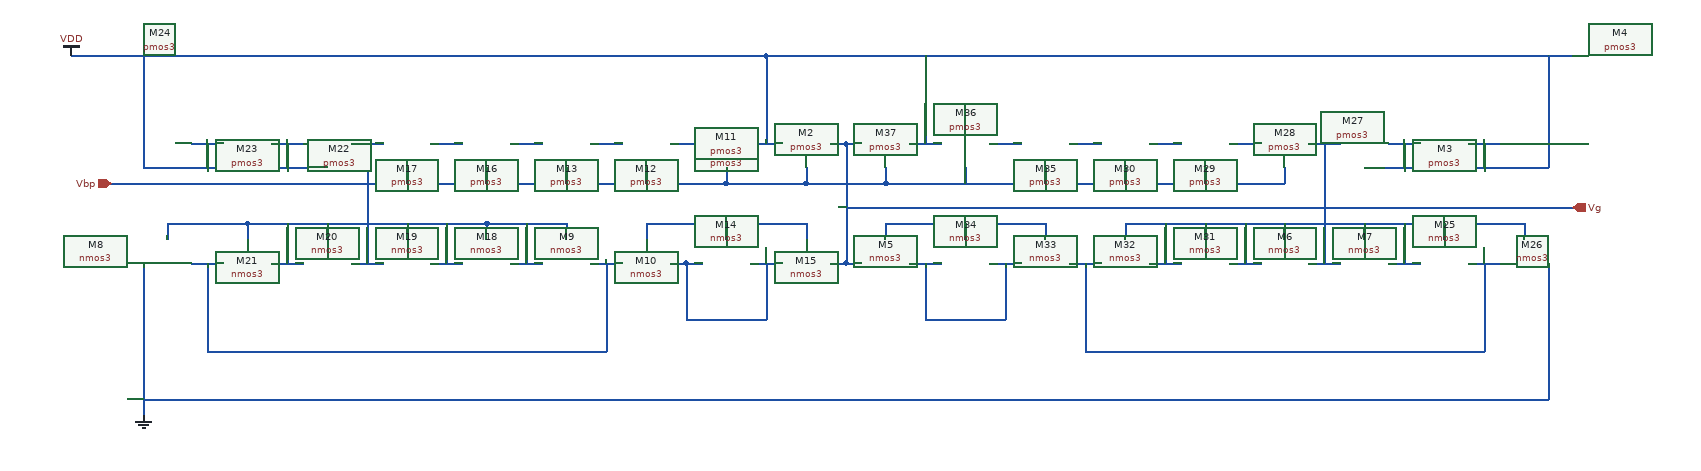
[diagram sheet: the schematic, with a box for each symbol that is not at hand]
v {xschem version=2.9.9 file_version=1.2 }
G {}
K {}
V {}
S {}
E {}
N 1330 -540 1330 -520 { lab=Vbp}
N 1330 -520 1430 -520 { lab=Vbp}
N 1430 -540 1430 -520 { lab=Vbp}
N 1110 -520 1330 -520 { lab=Vbp}
N 1360 -570 1400 -570 { lab=VDD}
N 1380 -680 1380 -570 { lab=VDD}
N 1110 -680 1380 -680 { lab=VDD}
N 1460 -570 1480 -570 { lab=Vg}
N 1480 -570 1480 -420 { lab=Vg}
N 1260 -420 1280 -420 { lab=#net1}
N 1230 -470 1230 -450 { lab=#net2}
N 1230 -470 1280 -470 { lab=#net2}
N 1160 -420 1200 -420 { lab=#net3}
N 1180 -420 1180 -340 { lab=#net3}
N 630 -470 630 -450 { lab=#net4}
N 1030 -470 1130 -470 { lab=#net4}
N 1130 -470 1130 -450 { lab=#net4}
N 1280 -420 1300 -420 { lab=#net1}
N 1280 -420 1280 -350 { lab=#net1}
N 1280 -350 1380 -350 { lab=#net1}
N 1380 -420 1380 -350 { lab=#net1}
N 1360 -420 1400 -420 { lab=#net1}
N 1280 -470 1430 -470 { lab=#net2}
N 1430 -470 1430 -450 { lab=#net2}
N 1330 -470 1330 -450 { lab=#net2}
N 1460 -420 1480 -420 { lab=Vg}
N 850 -680 1110 -680 { lab=VDD}
N 850 -520 1110 -520 { lab=Vbp}
N 1260 -570 1300 -570 { lab=#net5}
N 1160 -570 1200 -570 { lab=#net6}
N 1060 -570 1100 -570 { lab=#net7}
N 960 -570 1000 -570 { lab=#net8}
N 930 -540 930 -520 { lab=Vbp}
N 1030 -540 1030 -520 { lab=Vbp}
N 1130 -540 1130 -520 { lab=Vbp}
N 1230 -540 1230 -520 { lab=Vbp}
N 960 -420 1000 -420 { lab=#net4}
N 860 -420 900 -420 { lab=#net4}
N 760 -420 800 -420 { lab=#net4}
N 1180 -340 1180 -310 { lab=#net3}
N 1060 -420 1100 -420 { lab=#net4}
N 730 -470 1030 -470 { lab=#net4}
N 730 -470 730 -450 { lab=#net4}
N 830 -470 830 -450 { lab=#net4}
N 930 -470 930 -450 { lab=#net4}
N 1030 -470 1030 -450 { lab=#net4}
N 1080 -470 1080 -420 { lab=#net4}
N 980 -470 980 -420 { lab=#net4}
N 880 -470 880 -420 { lab=#net4}
N 780 -470 780 -420 { lab=#net4}
N 630 -470 730 -470 { lab=#net4}
N 660 -420 700 -420 { lab=#net3}
N 680 -420 680 -310 { lab=#net3}
N 680 -310 1180 -310 { lab=#net3}
N 880 -570 900 -570 { lab=#net4}
N 880 -570 880 -470 { lab=#net4}
N 560 -520 850 -520 { lab=Vbp}
N 860 -570 880 -570 { lab=#net4}
N 760 -570 800 -570 { lab=VDD}
N 660 -570 700 -570 { lab=VDD}
N 600 -570 600 -540 { lab=VDD}
N 600 -540 830 -540 { lab=VDD}
N 600 -680 600 -570 { lab=VDD}
N 510 -680 850 -680 { lab=VDD}
N 680 -570 680 -540 { lab=VDD}
N 780 -570 780 -540 { lab=VDD}
N 1480 -420 1500 -420 { lab=Vg}
N 1480 -570 1500 -570 { lab=Vg}
N 1560 -570 1600 -570 { lab=VDD}
N 1560 -420 1600 -420 { lab=#net9}
N 1660 -570 1700 -570 { lab=#net10}
N 1660 -420 1700 -420 { lab=#net9}
N 1760 -570 1800 -570 { lab=#net11}
N 1760 -420 1800 -420 { lab=#net12}
N 1860 -570 1900 -570 { lab=#net13}
N 1860 -420 1900 -420 { lab=#net14}
N 1960 -570 2000 -570 { lab=#net15}
N 1960 -420 2000 -420 { lab=#net14}
N 2060 -570 2100 -570 { lab=#net14}
N 2060 -420 2100 -420 { lab=#net14}
N 2160 -570 2200 -570 { lab=VDD}
N 2160 -420 2200 -420 { lab=#net14}
N 2260 -570 2300 -570 { lab=VDD}
N 2260 -420 2300 -420 { lab=#net12}
N 1530 -470 1530 -450 { lab=#net16}
N 1530 -470 1730 -470 { lab=#net16}
N 1730 -470 1730 -450 { lab=#net16}
N 1630 -470 1630 -450 { lab=#net16}
N 1580 -420 1580 -350 { lab=#net9}
N 1580 -350 1680 -350 { lab=#net9}
N 1680 -420 1680 -350 { lab=#net9}
N 1580 -680 1580 -570 { lab=VDD}
N 1380 -680 2390 -680 { lab=VDD}
N 1530 -540 1530 -520 { lab=Vbp}
N 1530 -520 2030 -520 { lab=Vbp}
N 2030 -540 2030 -520 { lab=Vbp}
N 1630 -540 1630 -520 { lab=Vbp}
N 1730 -540 1730 -520 { lab=Vbp}
N 1830 -540 1830 -520 { lab=Vbp}
N 1930 -540 1930 -520 { lab=Vbp}
N 1430 -520 1530 -520 { lab=Vbp}
N 2130 -540 2230 -540 { lab=VDD}
N 2230 -540 2330 -540 { lab=VDD}
N 2330 -540 2360 -540 { lab=VDD}
N 2360 -680 2360 -540 { lab=VDD}
N 2180 -570 2180 -540 { lab=VDD}
N 2280 -570 2280 -540 { lab=VDD}
N 1780 -420 1780 -310 { lab=#net12}
N 1780 -310 2280 -310 { lab=#net12}
N 2280 -420 2280 -310 { lab=#net12}
N 2360 -420 2360 -250 { lab=#net17}
N 1830 -470 1830 -450 { lab=#net14}
N 1830 -470 2330 -470 { lab=#net14}
N 2330 -470 2330 -450 { lab=#net14}
N 2230 -470 2230 -450 { lab=#net14}
N 2130 -470 2130 -450 { lab=#net14}
N 2030 -470 2030 -450 { lab=#net14}
N 1930 -470 1930 -450 { lab=#net14}
N 1880 -470 1880 -420 { lab=#net14}
N 1980 -470 1980 -420 { lab=#net14}
N 2080 -470 2080 -420 { lab=#net14}
N 2180 -470 2180 -420 { lab=#net14}
N 2080 -570 2080 -470 { lab=#net14}
N 1480 -490 2390 -490 { lab=Vg}
N 600 -420 600 -230 { lab=#net18}
N 600 -250 2360 -250 {}
C {madvlsi/pmos3.sym} 1330 -570 3 0 {name=M1
L=1
W=1.5
body=VDD
nf=1
mult=1
ad="'int((nf+1)/2) * W/nf * 0.29'" 
pd="'2*int((nf+1)/2) * (W/nf + 0.29)'"
as="'int((nf+2)/2) * W/nf * 0.29'" 
ps="'2*int((nf+2)/2) * (W/nf + 0.29)'"
nrd="'0.29 / W'" nrs="'0.29 / W'"
sa=0 sb=0 sd=0
model=pfet_01v8
spiceprefix=X
}
C {madvlsi/pmos3.sym} 1430 -570 3 0 {name=M2
L=1
W=1.5
body=VDD
nf=1
mult=1
ad="'int((nf+1)/2) * W/nf * 0.29'" 
pd="'2*int((nf+1)/2) * (W/nf + 0.29)'"
as="'int((nf+2)/2) * W/nf * 0.29'" 
ps="'2*int((nf+2)/2) * (W/nf + 0.29)'"
nrd="'0.29 / W'" nrs="'0.29 / W'"
sa=0 sb=0 sd=0
model=pfet_01v8
spiceprefix=X
}
C {madvlsi/nmos3.sym} 630 -420 1 0 {name=M8
L=1
W=3
body=GND
nf=1
mult=3
ad="'int((nf+1)/2) * W/nf * 0.29'" 
pd="'2*int((nf+1)/2) * (W/nf + 0.29)'"
as="'int((nf+2)/2) * W/nf * 0.29'" 
ps="'2*int((nf+2)/2) * (W/nf + 0.29)'"
nrd="'0.29 / W'" nrs="'0.29 / W'"
sa=0 sb=0 sd=0
model=nfet_01v8
spiceprefix=X
}
C {madvlsi/nmos3.sym} 1130 -420 1 0 {name=M9
L=1
W=3
body=GND
nf=1
mult=3
ad="'int((nf+1)/2) * W/nf * 0.29'" 
pd="'2*int((nf+1)/2) * (W/nf + 0.29)'"
as="'int((nf+2)/2) * W/nf * 0.29'" 
ps="'2*int((nf+2)/2) * (W/nf + 0.29)'"
nrd="'0.29 / W'" nrs="'0.29 / W'"
sa=0 sb=0 sd=0
model=nfet_01v8
spiceprefix=X
}
C {madvlsi/nmos3.sym} 1230 -420 1 0 {name=M10
L=1
W=3
body=GND
nf=1
mult=3
ad="'int((nf+1)/2) * W/nf * 0.29'" 
pd="'2*int((nf+1)/2) * (W/nf + 0.29)'"
as="'int((nf+2)/2) * W/nf * 0.29'" 
ps="'2*int((nf+2)/2) * (W/nf + 0.29)'"
nrd="'0.29 / W'" nrs="'0.29 / W'"
sa=0 sb=0 sd=0
model=nfet_01v8
spiceprefix=X
}
C {madvlsi/vdd.sym} 510 -680 0 0 {name=l1 lab=VDD}
C {madvlsi/pmos3.sym} 1330 -570 3 0 {name=M11
L=1
W=1.5
body=VDD
nf=1
mult=1
ad="'int((nf+1)/2) * W/nf * 0.29'" 
pd="'2*int((nf+1)/2) * (W/nf + 0.29)'"
as="'int((nf+2)/2) * W/nf * 0.29'" 
ps="'2*int((nf+2)/2) * (W/nf + 0.29)'"
nrd="'0.29 / W'" nrs="'0.29 / W'"
sa=0 sb=0 sd=0
model=pfet_01v8
spiceprefix=X
}
C {devices/ipin.sym} 560 -520 0 0 {name=p1 lab=Vbp}
C {madvlsi/gnd.sym} 600 -230 0 0 {name=l2 lab=GND}
C {devices/opin.sym} 2390 -490 0 0 {name=p2 lab=Vg}
C {madvlsi/nmos3.sym} 1330 -420 1 0 {name=M14
L=1
W=3
body=GND
nf=1
mult=3
ad="'int((nf+1)/2) * W/nf * 0.29'" 
pd="'2*int((nf+1)/2) * (W/nf + 0.29)'"
as="'int((nf+2)/2) * W/nf * 0.29'" 
ps="'2*int((nf+2)/2) * (W/nf + 0.29)'"
nrd="'0.29 / W'" nrs="'0.29 / W'"
sa=0 sb=0 sd=0
model=nfet_01v8
spiceprefix=X
}
C {madvlsi/nmos3.sym} 1430 -420 1 0 {name=M15
L=1
W=3
body=GND
nf=1
mult=3
ad="'int((nf+1)/2) * W/nf * 0.29'" 
pd="'2*int((nf+1)/2) * (W/nf + 0.29)'"
as="'int((nf+2)/2) * W/nf * 0.29'" 
ps="'2*int((nf+2)/2) * (W/nf + 0.29)'"
nrd="'0.29 / W'" nrs="'0.29 / W'"
sa=0 sb=0 sd=0
model=nfet_01v8
spiceprefix=X
}
C {madvlsi/pmos3.sym} 1230 -570 3 0 {name=M12
L=1
W=1.5
body=VDD
nf=1
mult=1
ad="'int((nf+1)/2) * W/nf * 0.29'" 
pd="'2*int((nf+1)/2) * (W/nf + 0.29)'"
as="'int((nf+2)/2) * W/nf * 0.29'" 
ps="'2*int((nf+2)/2) * (W/nf + 0.29)'"
nrd="'0.29 / W'" nrs="'0.29 / W'"
sa=0 sb=0 sd=0
model=pfet_01v8
spiceprefix=X
}
C {madvlsi/pmos3.sym} 1130 -570 3 0 {name=M13
L=1
W=1.5
body=VDD
nf=1
mult=1
ad="'int((nf+1)/2) * W/nf * 0.29'" 
pd="'2*int((nf+1)/2) * (W/nf + 0.29)'"
as="'int((nf+2)/2) * W/nf * 0.29'" 
ps="'2*int((nf+2)/2) * (W/nf + 0.29)'"
nrd="'0.29 / W'" nrs="'0.29 / W'"
sa=0 sb=0 sd=0
model=pfet_01v8
spiceprefix=X
}
C {madvlsi/pmos3.sym} 1030 -570 3 0 {name=M16
L=1
W=1.5
body=VDD
nf=1
mult=1
ad="'int((nf+1)/2) * W/nf * 0.29'" 
pd="'2*int((nf+1)/2) * (W/nf + 0.29)'"
as="'int((nf+2)/2) * W/nf * 0.29'" 
ps="'2*int((nf+2)/2) * (W/nf + 0.29)'"
nrd="'0.29 / W'" nrs="'0.29 / W'"
sa=0 sb=0 sd=0
model=pfet_01v8
spiceprefix=X
}
C {madvlsi/pmos3.sym} 930 -570 3 0 {name=M17
L=1
W=1.5
body=VDD
nf=1
mult=1
ad="'int((nf+1)/2) * W/nf * 0.29'" 
pd="'2*int((nf+1)/2) * (W/nf + 0.29)'"
as="'int((nf+2)/2) * W/nf * 0.29'" 
ps="'2*int((nf+2)/2) * (W/nf + 0.29)'"
nrd="'0.29 / W'" nrs="'0.29 / W'"
sa=0 sb=0 sd=0
model=pfet_01v8
spiceprefix=X
}
C {madvlsi/nmos3.sym} 1030 -420 1 0 {name=M18
L=1
W=3
body=GND
nf=1
mult=3
ad="'int((nf+1)/2) * W/nf * 0.29'" 
pd="'2*int((nf+1)/2) * (W/nf + 0.29)'"
as="'int((nf+2)/2) * W/nf * 0.29'" 
ps="'2*int((nf+2)/2) * (W/nf + 0.29)'"
nrd="'0.29 / W'" nrs="'0.29 / W'"
sa=0 sb=0 sd=0
model=nfet_01v8
spiceprefix=X
}
C {madvlsi/nmos3.sym} 930 -420 1 0 {name=M19
L=1
W=3
body=GND
nf=1
mult=3
ad="'int((nf+1)/2) * W/nf * 0.29'" 
pd="'2*int((nf+1)/2) * (W/nf + 0.29)'"
as="'int((nf+2)/2) * W/nf * 0.29'" 
ps="'2*int((nf+2)/2) * (W/nf + 0.29)'"
nrd="'0.29 / W'" nrs="'0.29 / W'"
sa=0 sb=0 sd=0
model=nfet_01v8
spiceprefix=X
}
C {madvlsi/nmos3.sym} 830 -420 1 0 {name=M20
L=1
W=3
body=GND
nf=1
mult=3
ad="'int((nf+1)/2) * W/nf * 0.29'" 
pd="'2*int((nf+1)/2) * (W/nf + 0.29)'"
as="'int((nf+2)/2) * W/nf * 0.29'" 
ps="'2*int((nf+2)/2) * (W/nf + 0.29)'"
nrd="'0.29 / W'" nrs="'0.29 / W'"
sa=0 sb=0 sd=0
model=nfet_01v8
spiceprefix=X
}
C {madvlsi/nmos3.sym} 730 -420 1 0 {name=M21
L=1
W=3
body=GND
nf=1
mult=3
ad="'int((nf+1)/2) * W/nf * 0.29'" 
pd="'2*int((nf+1)/2) * (W/nf + 0.29)'"
as="'int((nf+2)/2) * W/nf * 0.29'" 
ps="'2*int((nf+2)/2) * (W/nf + 0.29)'"
nrd="'0.29 / W'" nrs="'0.29 / W'"
sa=0 sb=0 sd=0
model=nfet_01v8
spiceprefix=X
}
C {madvlsi/pmos3.sym} 830 -570 3 0 {name=M22
L=1
W=1.5
body=VDD
nf=1
mult=1
ad="'int((nf+1)/2) * W/nf * 0.29'" 
pd="'2*int((nf+1)/2) * (W/nf + 0.29)'"
as="'int((nf+2)/2) * W/nf * 0.29'" 
ps="'2*int((nf+2)/2) * (W/nf + 0.29)'"
nrd="'0.29 / W'" nrs="'0.29 / W'"
sa=0 sb=0 sd=0
model=pfet_01v8
spiceprefix=X
}
C {madvlsi/pmos3.sym} 730 -570 3 0 {name=M23
L=1
W=1.5
body=VDD
nf=1
mult=1
ad="'int((nf+1)/2) * W/nf * 0.29'" 
pd="'2*int((nf+1)/2) * (W/nf + 0.29)'"
as="'int((nf+2)/2) * W/nf * 0.29'" 
ps="'2*int((nf+2)/2) * (W/nf + 0.29)'"
nrd="'0.29 / W'" nrs="'0.29 / W'"
sa=0 sb=0 sd=0
model=pfet_01v8
spiceprefix=X
}
C {madvlsi/pmos3.sym} 630 -570 3 0 {name=M24
L=1
W=1.5
body=VDD
nf=1
mult=1
ad="'int((nf+1)/2) * W/nf * 0.29'" 
pd="'2*int((nf+1)/2) * (W/nf + 0.29)'"
as="'int((nf+2)/2) * W/nf * 0.29'" 
ps="'2*int((nf+2)/2) * (W/nf + 0.29)'"
nrd="'0.29 / W'" nrs="'0.29 / W'"
sa=0 sb=0 sd=0
model=pfet_01v8
spiceprefix=X
}
C {madvlsi/pmos3.sym} 2230 -570 3 0 {name=M3
L=1
W=1.5
body=VDD
nf=1
mult=1
ad="'int((nf+1)/2) * W/nf * 0.29'" 
pd="'2*int((nf+1)/2) * (W/nf + 0.29)'"
as="'int((nf+2)/2) * W/nf * 0.29'" 
ps="'2*int((nf+2)/2) * (W/nf + 0.29)'"
nrd="'0.29 / W'" nrs="'0.29 / W'"
sa=0 sb=0 sd=0
model=pfet_01v8
spiceprefix=X
}
C {madvlsi/pmos3.sym} 2330 -570 3 0 {name=M4
L=1
W=1.5
body=VDD
nf=1
mult=1
ad="'int((nf+1)/2) * W/nf * 0.29'" 
pd="'2*int((nf+1)/2) * (W/nf + 0.29)'"
as="'int((nf+2)/2) * W/nf * 0.29'" 
ps="'2*int((nf+2)/2) * (W/nf + 0.29)'"
nrd="'0.29 / W'" nrs="'0.29 / W'"
sa=0 sb=0 sd=0
model=pfet_01v8
spiceprefix=X
}
C {madvlsi/nmos3.sym} 1530 -420 1 0 {name=M5
L=1
W=3
body=GND
nf=1
mult=3
ad="'int((nf+1)/2) * W/nf * 0.29'" 
pd="'2*int((nf+1)/2) * (W/nf + 0.29)'"
as="'int((nf+2)/2) * W/nf * 0.29'" 
ps="'2*int((nf+2)/2) * (W/nf + 0.29)'"
nrd="'0.29 / W'" nrs="'0.29 / W'"
sa=0 sb=0 sd=0
model=nfet_01v8
spiceprefix=X
}
C {madvlsi/nmos3.sym} 2030 -420 1 0 {name=M6
L=1
W=3
body=GND
nf=1
mult=3
ad="'int((nf+1)/2) * W/nf * 0.29'" 
pd="'2*int((nf+1)/2) * (W/nf + 0.29)'"
as="'int((nf+2)/2) * W/nf * 0.29'" 
ps="'2*int((nf+2)/2) * (W/nf + 0.29)'"
nrd="'0.29 / W'" nrs="'0.29 / W'"
sa=0 sb=0 sd=0
model=nfet_01v8
spiceprefix=X
}
C {madvlsi/nmos3.sym} 2130 -420 1 0 {name=M7
L=1
W=3
body=GND
nf=1
mult=3
ad="'int((nf+1)/2) * W/nf * 0.29'" 
pd="'2*int((nf+1)/2) * (W/nf + 0.29)'"
as="'int((nf+2)/2) * W/nf * 0.29'" 
ps="'2*int((nf+2)/2) * (W/nf + 0.29)'"
nrd="'0.29 / W'" nrs="'0.29 / W'"
sa=0 sb=0 sd=0
model=nfet_01v8
spiceprefix=X
}
C {madvlsi/nmos3.sym} 2230 -420 1 0 {name=M25
L=1
W=3
body=GND
nf=1
mult=3
ad="'int((nf+1)/2) * W/nf * 0.29'" 
pd="'2*int((nf+1)/2) * (W/nf + 0.29)'"
as="'int((nf+2)/2) * W/nf * 0.29'" 
ps="'2*int((nf+2)/2) * (W/nf + 0.29)'"
nrd="'0.29 / W'" nrs="'0.29 / W'"
sa=0 sb=0 sd=0
model=nfet_01v8
spiceprefix=X
}
C {madvlsi/nmos3.sym} 2330 -420 1 0 {name=M26
L=1
W=3
body=GND
nf=1
mult=3
ad="'int((nf+1)/2) * W/nf * 0.29'" 
pd="'2*int((nf+1)/2) * (W/nf + 0.29)'"
as="'int((nf+2)/2) * W/nf * 0.29'" 
ps="'2*int((nf+2)/2) * (W/nf + 0.29)'"
nrd="'0.29 / W'" nrs="'0.29 / W'"
sa=0 sb=0 sd=0
model=nfet_01v8
spiceprefix=X
}
C {madvlsi/pmos3.sym} 2130 -570 3 0 {name=M27
L=1
W=1.5
body=VDD
nf=1
mult=1
ad="'int((nf+1)/2) * W/nf * 0.29'" 
pd="'2*int((nf+1)/2) * (W/nf + 0.29)'"
as="'int((nf+2)/2) * W/nf * 0.29'" 
ps="'2*int((nf+2)/2) * (W/nf + 0.29)'"
nrd="'0.29 / W'" nrs="'0.29 / W'"
sa=0 sb=0 sd=0
model=pfet_01v8
spiceprefix=X
}
C {madvlsi/pmos3.sym} 2030 -570 3 0 {name=M28
L=1
W=1.5
body=VDD
nf=1
mult=1
ad="'int((nf+1)/2) * W/nf * 0.29'" 
pd="'2*int((nf+1)/2) * (W/nf + 0.29)'"
as="'int((nf+2)/2) * W/nf * 0.29'" 
ps="'2*int((nf+2)/2) * (W/nf + 0.29)'"
nrd="'0.29 / W'" nrs="'0.29 / W'"
sa=0 sb=0 sd=0
model=pfet_01v8
spiceprefix=X
}
C {madvlsi/pmos3.sym} 1930 -570 3 0 {name=M29
L=1
W=1.5
body=VDD
nf=1
mult=1
ad="'int((nf+1)/2) * W/nf * 0.29'" 
pd="'2*int((nf+1)/2) * (W/nf + 0.29)'"
as="'int((nf+2)/2) * W/nf * 0.29'" 
ps="'2*int((nf+2)/2) * (W/nf + 0.29)'"
nrd="'0.29 / W'" nrs="'0.29 / W'"
sa=0 sb=0 sd=0
model=pfet_01v8
spiceprefix=X
}
C {madvlsi/pmos3.sym} 1830 -570 3 0 {name=M30
L=1
W=1.5
body=VDD
nf=1
mult=1
ad="'int((nf+1)/2) * W/nf * 0.29'" 
pd="'2*int((nf+1)/2) * (W/nf + 0.29)'"
as="'int((nf+2)/2) * W/nf * 0.29'" 
ps="'2*int((nf+2)/2) * (W/nf + 0.29)'"
nrd="'0.29 / W'" nrs="'0.29 / W'"
sa=0 sb=0 sd=0
model=pfet_01v8
spiceprefix=X
}
C {madvlsi/nmos3.sym} 1930 -420 1 0 {name=M31
L=1
W=3
body=GND
nf=1
mult=3
ad="'int((nf+1)/2) * W/nf * 0.29'" 
pd="'2*int((nf+1)/2) * (W/nf + 0.29)'"
as="'int((nf+2)/2) * W/nf * 0.29'" 
ps="'2*int((nf+2)/2) * (W/nf + 0.29)'"
nrd="'0.29 / W'" nrs="'0.29 / W'"
sa=0 sb=0 sd=0
model=nfet_01v8
spiceprefix=X
}
C {madvlsi/nmos3.sym} 1830 -420 1 0 {name=M32
L=1
W=3
body=GND
nf=1
mult=3
ad="'int((nf+1)/2) * W/nf * 0.29'" 
pd="'2*int((nf+1)/2) * (W/nf + 0.29)'"
as="'int((nf+2)/2) * W/nf * 0.29'" 
ps="'2*int((nf+2)/2) * (W/nf + 0.29)'"
nrd="'0.29 / W'" nrs="'0.29 / W'"
sa=0 sb=0 sd=0
model=nfet_01v8
spiceprefix=X
}
C {madvlsi/nmos3.sym} 1730 -420 1 0 {name=M33
L=1
W=3
body=GND
nf=1
mult=3
ad="'int((nf+1)/2) * W/nf * 0.29'" 
pd="'2*int((nf+1)/2) * (W/nf + 0.29)'"
as="'int((nf+2)/2) * W/nf * 0.29'" 
ps="'2*int((nf+2)/2) * (W/nf + 0.29)'"
nrd="'0.29 / W'" nrs="'0.29 / W'"
sa=0 sb=0 sd=0
model=nfet_01v8
spiceprefix=X
}
C {madvlsi/nmos3.sym} 1630 -420 1 0 {name=M34
L=1
W=3
body=GND
nf=1
mult=3
ad="'int((nf+1)/2) * W/nf * 0.29'" 
pd="'2*int((nf+1)/2) * (W/nf + 0.29)'"
as="'int((nf+2)/2) * W/nf * 0.29'" 
ps="'2*int((nf+2)/2) * (W/nf + 0.29)'"
nrd="'0.29 / W'" nrs="'0.29 / W'"
sa=0 sb=0 sd=0
model=nfet_01v8
spiceprefix=X
}
C {madvlsi/pmos3.sym} 1730 -570 3 0 {name=M35
L=1
W=1.5
body=VDD
nf=1
mult=1
ad="'int((nf+1)/2) * W/nf * 0.29'" 
pd="'2*int((nf+1)/2) * (W/nf + 0.29)'"
as="'int((nf+2)/2) * W/nf * 0.29'" 
ps="'2*int((nf+2)/2) * (W/nf + 0.29)'"
nrd="'0.29 / W'" nrs="'0.29 / W'"
sa=0 sb=0 sd=0
model=pfet_01v8
spiceprefix=X
}
C {madvlsi/pmos3.sym} 1630 -570 3 0 {name=M36
L=1
W=1.5
body=VDD
nf=1
mult=1
ad="'int((nf+1)/2) * W/nf * 0.29'" 
pd="'2*int((nf+1)/2) * (W/nf + 0.29)'"
as="'int((nf+2)/2) * W/nf * 0.29'" 
ps="'2*int((nf+2)/2) * (W/nf + 0.29)'"
nrd="'0.29 / W'" nrs="'0.29 / W'"
sa=0 sb=0 sd=0
model=pfet_01v8
spiceprefix=X
}
C {madvlsi/pmos3.sym} 1530 -570 3 0 {name=M37
L=1
W=1.5
body=VDD
nf=1
mult=1
ad="'int((nf+1)/2) * W/nf * 0.29'" 
pd="'2*int((nf+1)/2) * (W/nf + 0.29)'"
as="'int((nf+2)/2) * W/nf * 0.29'" 
ps="'2*int((nf+2)/2) * (W/nf + 0.29)'"
nrd="'0.29 / W'" nrs="'0.29 / W'"
sa=0 sb=0 sd=0
model=pfet_01v8
spiceprefix=X
}
